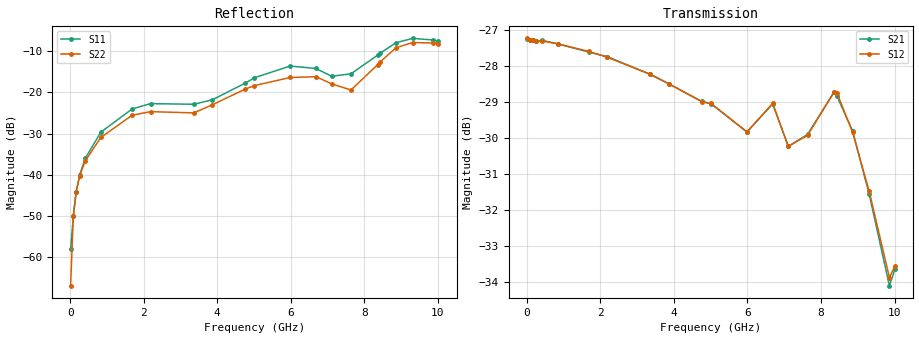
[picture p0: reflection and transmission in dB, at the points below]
! Device ID: PE43705
! Serial: 1
! Insertion: A
! Impedance: 50 ohm
! Temp: 25C
! VDD: 3.400V
! Attenuation Step: 26.25dB
#  Hz  S  RI  R  50
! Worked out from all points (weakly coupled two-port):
!   401 points, 10 MHz to 10.01 GHz, reference 50 ohm
!   highest |S21| = -27.25 dB at 10 MHz (marker M1); lowest = -34.1 dB at 9.86 GHz (marker M2)
!   lowest |S11| = -58.1 dB at 10 MHz (marker M3), VSWR 1.00, Z = 49.9 + j0.0376 ohm
!   |S11| at or under -10 dB: start of sweep to 8.492 GHz
!   |S22| runs from -66.9 to -7.8 dB; largest |S21 - S12| = 0.0007
!   S11 on the Smith chart (normalised r, x): 10 MHz: 1.00, +0.00; 4.76 GHz: 0.80, +0.12; 8.435 GHz: 0.80, +0.53; 9.31 GHz: 0.52, +0.55; 10.01 GHz: 0.47, +0.33
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1e7  -0.00119 0.000377  0.0434 -0.000171  0.0435 -0.000131  -0.000196 0.000408
8.5e7  -0.000985 0.00301  0.0433 -0.000996  0.0432 -0.00102  0.000323 0.00315
1.6e8  -0.00146 0.00598  0.0432 -0.00184  0.0432 -0.00181  7.61e-05 0.00614
2.6e8  -0.00275 0.00968  0.043 -0.00294  0.043 -0.00291  -0.000952 0.00976
4.1e8  -0.00596 0.0148  0.043 -0.00439  0.0429 -0.00462  -0.00368 0.0144
8.35e8  -0.0237 0.023  0.0418 -0.00896  0.0418 -0.00897  -0.0184 0.0218
1.685e9  -0.0624 0.0102  0.038 -0.017  0.0381 -0.017  -0.0516 0.0119
2.185e9  -0.0731 -0.00494  0.0352 -0.0211  0.0351 -0.0211  -0.0586 0.000822
3.36e9  -0.0719 -0.00328  0.0265 -0.0283  0.0266 -0.0282  -0.0563 0.005
3.86e9  -0.0786 0.0215  0.0227 -0.03  0.0227 -0.03  -0.0678 0.0202
4.76e9  -0.1058 0.0749  0.0165 -0.0315  0.0166 -0.0314  -0.0963 0.0532
5.01e9  -0.1215 0.0899  0.0153 -0.0318  0.0154 -0.0318  -0.1055 0.0597
5.985e9  -0.1755 0.1143  0.00855 -0.0311  0.00861 -0.0311  -0.1318 0.0761
6.685e9  -0.1669 0.1018  0.00579 -0.0348  0.00564 -0.0349  -0.1382 0.0709
7.11e9  -0.1317 0.0862  0.000392 -0.0308  0.000321 -0.0308  -0.105 0.0724
7.635e9  -0.0827 0.1468  0.000904 -0.032  0.000968 -0.0319  -0.0548 0.0921
8.36e9  -0.0227 0.2827  -0.00844 -0.0357  -0.00842 -0.0357  -0.0334 0.2148
8.435e9  -0.0249 0.3001  -0.0101 -0.0347  -0.0101 -0.0351  -0.0365 0.2333
8.86e9  -0.0751 0.394  -0.0151 -0.0286  -0.015 -0.0285  -0.0941 0.3364
9.31e9  -0.1615 0.424  -0.0145 -0.0221  -0.0148 -0.0222  -0.1864 0.358
9.86e9  -0.2764 0.3347  -0.00661 -0.0186  -0.00701 -0.019  -0.3147 0.2452
1.001e10  -0.2991 0.2898  -0.00412 -0.0204  -0.00419 -0.0206  -0.3446 0.1855
